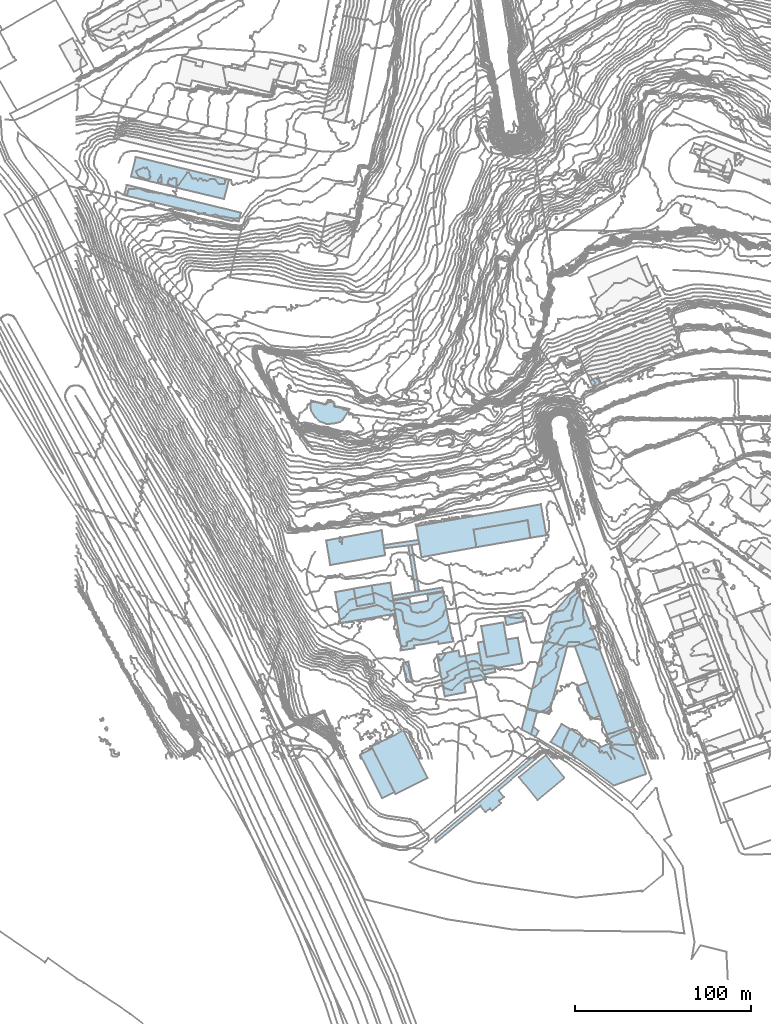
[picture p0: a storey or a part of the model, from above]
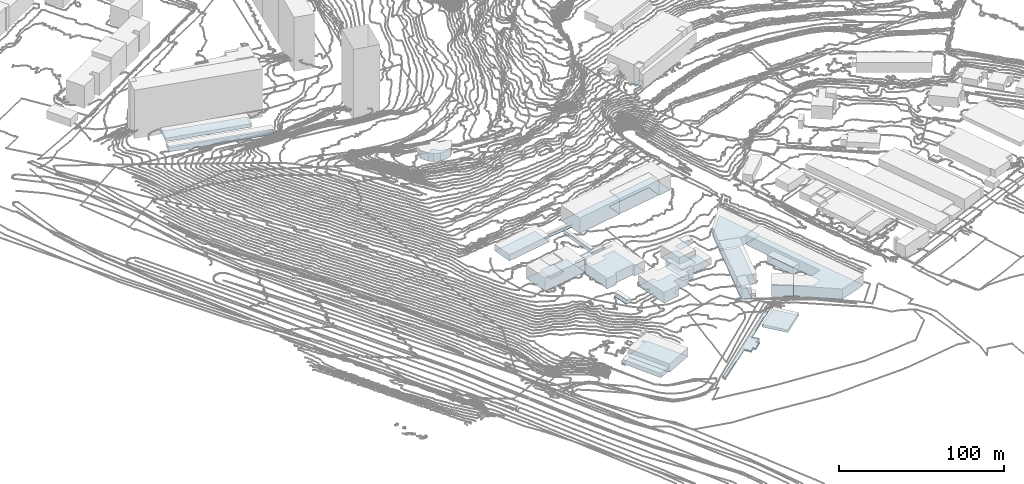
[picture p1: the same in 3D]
Properties of the parts of a building model (IFC2X3)

# File
Description: ViewDefinition [CoordinationView]
Time: 2024-08-21T15:23:12
Written by: TpxIfclib v0.1
Made in: TpxIfclib v0.1

# IfcFooting (1174)
In: Topoexport Data
PredefinedType: STRIP_FOOTING
